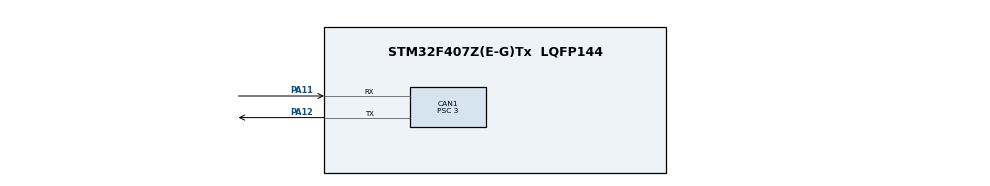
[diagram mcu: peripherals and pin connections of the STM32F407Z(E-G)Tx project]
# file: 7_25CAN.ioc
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CAN1.BS1=CAN_BS1_12TQ
CAN1.CalculateBaudRate=1000000
CAN1.CalculateTimeBit=1000
CAN1.CalculateTimeQuantum=71.42857142857143
CAN1.Prescaler=3
Mcu.Family=STM32F4
Mcu.Name=STM32F407Z(E-G)Tx
Mcu.Package=LQFP144
NVIC.CAN1_RX0_IRQn=true\:0\:0\:false\:false\:true\:true\:true\:true
NVIC.PriorityGroup=NVIC_PRIORITYGROUP_4
PA11.Mode=CAN_Activate
PA11.Signal=CAN1_RX
PA12.Mode=CAN_Activate
PA12.Signal=CAN1_TX
PA13.Mode=Serial_Wire
PA13.Signal=SYS_JTMS-SWDIO
PA14.Mode=Serial_Wire
PA14.Signal=SYS_JTCK-SWCLK
PH0-OSC_IN.Mode=HSE-External-Oscillator
PH0-OSC_IN.Signal=RCC_OSC_IN
PH1-OSC_OUT.Mode=HSE-External-Oscillator
PH1-OSC_OUT.Signal=RCC_OSC_OUT
ProjectManager.HeapSize=0x200
ProjectManager.StackSize=0x400
ProjectManager.TargetToolchain=MDK-ARM V5
RCC.48MHZClocksFreq_Value=84000000
RCC.AHBFreq_Value=168000000
RCC.APB1CLKDivider=RCC_HCLK_DIV4
RCC.APB1Freq_Value=42000000
RCC.APB1TimFreq_Value=84000000
RCC.APB2CLKDivider=RCC_HCLK_DIV2
RCC.APB2Freq_Value=84000000
RCC.APB2TimFreq_Value=168000000
RCC.CortexFreq_Value=168000000
RCC.HCLKFreq_Value=168000000
RCC.HSE_VALUE=12000000
RCC.HSI_VALUE=16000000
RCC.LSE_VALUE=32768
RCC.PLLM=6
RCC.PLLN=168
RCC.PLLSourceVirtual=RCC_PLLSOURCE_HSE
RCC.SYSCLKFreq_VALUE=168000000
RCC.SYSCLKSource=RCC_SYSCLKSOURCE_PLLCLK
RCC.VCOOutputFreq_Value=336000000
board=custom

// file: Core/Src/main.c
/* USER CODE BEGIN Header */
/**
  ******************************************************************************
  * @file           : main.c
  * @brief          : Main program body
  ******************************************************************************
  * @attention
  *
  * Copyright (c) 2022 STMicroelectronics.
  * All rights reserved.
  *
  * This software is licensed under terms that can be found in the LICENSE file
  * in the root directory of this software component.
  * If no LICENSE file comes with this software, it is provided AS-IS.
  *
  ******************************************************************************
  */
/* USER CODE END Header */
#include "main.h"
#include "can.h"
#include "gpio.h"

void SystemClock_Config(void);

int main(void)
{
  /* USER CODE BEGIN 1 */
CAN_TxHeaderTypeDef chassis_tx_message;
CAN_FilterTypeDef  sFilterConfig;
uint32_t send_mail_box;
int16_t	motor1 = 1000;
uint8_t chassis_can_send_data[8] = {0};
  /* USER CODE END 1 */

  /* MCU Configuration--------------------------------------------------------*/

  /* Reset of all peripherals, Initializes the Flash interface and the Systick. */
  HAL_Init();

  /* Configure the system clock */
  SystemClock_Config();

  /* Initialize all configured peripherals */
  MX_GPIO_Init();
  MX_CAN1_Init();
  /* USER CODE BEGIN 2 */
  HAL_CAN_Start(&hcan1);

    chassis_tx_message.StdId = 0x200;
    chassis_tx_message.IDE = CAN_ID_STD;
		chassis_tx_message.ExtId=0x12;        //��չ��ʶ��(29λ)
    chassis_tx_message.RTR = CAN_RTR_DATA;
    chassis_tx_message.DLC = 0x08;
    chassis_can_send_data[0] = motor1 >> 8;
    chassis_can_send_data[1] = motor1;
    chassis_can_send_data[2] = 0;
    chassis_can_send_data[3] = 0;
    chassis_can_send_data[4] = 0;
    chassis_can_send_data[5] = 0;
    chassis_can_send_data[6] = 0;
    chassis_can_send_data[7] = 0;

		HAL_CAN_AddTxMessage(&hcan1, &chassis_tx_message, chassis_can_send_data, &send_mail_box);

  /*##-2- Configure the CAN Filter ###########################################*/
  sFilterConfig.FilterBank = 0;
  sFilterConfig.FilterMode = CAN_FILTERMODE_IDMASK;
  sFilterConfig.FilterScale = CAN_FILTERSCALE_32BIT;
  sFilterConfig.FilterIdHigh = 0x0000;
  sFilterConfig.FilterIdLow = 0x0000;
  sFilterConfig.FilterMaskIdHigh = 0x0000;
  sFilterConfig.FilterMaskIdLow = 0x0000;
  sFilterConfig.FilterFIFOAssignment = CAN_RX_FIFO0;
  sFilterConfig.FilterActivation = ENABLE;
  sFilterConfig.SlaveStartFilterBank = 14;

	HAL_CAN_ConfigFilter(&hcan1, &sFilterConfig);
  /* USER CODE END 2 */

  /* Infinite loop */
  while (1)
  {

    /* USER CODE BEGIN 3 */
		HAL_CAN_AddTxMessage(&hcan1, &chassis_tx_message, chassis_can_send_data, &send_mail_box);
  }
  /* USER CODE END 3 */
}

void SystemClock_Config(void)
{
  RCC_OscInitTypeDef RCC_OscInitStruct = {0};
  RCC_ClkInitTypeDef RCC_ClkInitStruct = {0};

  /** Configure the main internal regulator output voltage
  */
  __HAL_RCC_PWR_CLK_ENABLE();
  __HAL_PWR_VOLTAGESCALING_CONFIG(PWR_REGULATOR_VOLTAGE_SCALE1);

  /** Initializes the RCC Oscillators according to the specified parameters
  * in the RCC_OscInitTypeDef structure.
  */
  RCC_OscInitStruct.OscillatorType = RCC_OSCILLATORTYPE_HSE;
  RCC_OscInitStruct.HSEState = RCC_HSE_ON;
  RCC_OscInitStruct.PLL.PLLState = RCC_PLL_ON;
  RCC_OscInitStruct.PLL.PLLSource = RCC_PLLSOURCE_HSE;
  RCC_OscInitStruct.PLL.PLLM = 8;
  RCC_OscInitStruct.PLL.PLLN = 336;
  RCC_OscInitStruct.PLL.PLLP = RCC_PLLP_DIV2;
  RCC_OscInitStruct.PLL.PLLQ = 7;
  if (HAL_RCC_OscConfig(&RCC_OscInitStruct) != HAL_OK)
  {
    Error_Handler();
  }

  /** Initializes the CPU, AHB and APB buses clocks
  */
  RCC_ClkInitStruct.ClockType = RCC_CLOCKTYPE_HCLK|RCC_CLOCKTYPE_SYSCLK
                              |RCC_CLOCKTYPE_PCLK1|RCC_CLOCKTYPE_PCLK2;
  RCC_ClkInitStruct.SYSCLKSource = RCC_SYSCLKSOURCE_PLLCLK;
  RCC_ClkInitStruct.AHBCLKDivider = RCC_SYSCLK_DIV1;
  RCC_ClkInitStruct.APB1CLKDivider = RCC_HCLK_DIV4;
  RCC_ClkInitStruct.APB2CLKDivider = RCC_HCLK_DIV2;

  if (HAL_RCC_ClockConfig(&RCC_ClkInitStruct, FLASH_LATENCY_5) != HAL_OK)
  {
    Error_Handler();
  }
}

void Error_Handler(void)
{
  __disable_irq();
  while (1)
  {
  }
}
